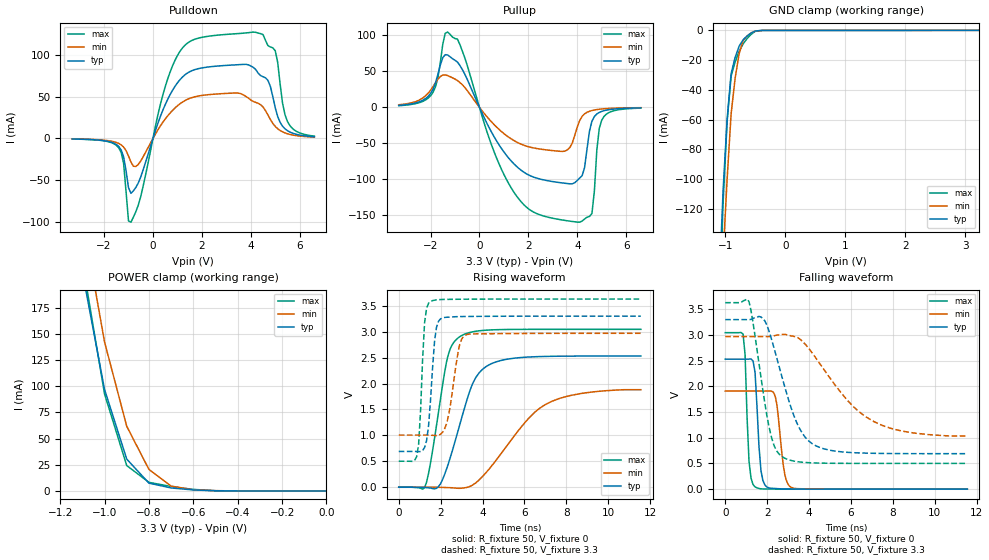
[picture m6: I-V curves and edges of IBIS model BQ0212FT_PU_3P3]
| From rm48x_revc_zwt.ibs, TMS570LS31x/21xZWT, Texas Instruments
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|   Model Cell BQ0212FT_PU_3P3
|BQ0212FT_PU_3P3
[Model]   BQ0212FT_PU_3P3
Model_type   I/O
Polarity   Non-Inverting
Enable   Active-Low
Vinl =  1.15
Vinh =  1.55
Cref =  15.0001pF
Rref =  101.0000M
Vref =  0V
Vmeas =  1.65
C_comp   1.2p   1.2p   1.2p
[Model Spec]
Vinl   1.15   1.02   1.28
Vinh   1.55   1.45   1.65
[Temperature Range]   25   155   -40
[Voltage Range]   3.3   2.97   3.63
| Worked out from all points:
|   slope of the pulldown table from 0 to 0.495 V, typ, clamps not added: 12.4 ohm
|   slope of the pullup table from 0 to 0.495 V, typ, clamps not added: 14.3 ohm
|   GND clamp passes 1 mA (typ) near -0.53 V on its own axis
|   POWER clamp passes 1 mA (typ) near -0.60 V on its own axis
|   rising waveform, R_fixture 50, V_fixture 0: 20-80 % time 1.15ns typ, 2.3ns min, 717ps max; typ from 0 V to 2.53 V
|   rising waveform, R_fixture 50, V_fixture 3.3: 20-80 % time 274ps typ, 441ps min, 219ps max; typ from 0.691 V to 3.3 V
|   falling waveform, R_fixture 50, V_fixture 0: 20-80 % time 219ps typ, 306ps min, 167ps max; typ from 2.53 V to 0 V
|   falling waveform, R_fixture 50, V_fixture 3.3: 20-80 % time 1.2ns typ, 2.39ns min, 725ps max; typ from 3.3 V to 0.691 V
[POWER_clamp]
|   voltage   I(typ)   I(min)   I(max)
-3.3V     3.99A      4.579A     4.788A
-1.1V     209.6mA    262.2mA    219.1mA
-1.067V   172.1mA    222.3mA    177mA
-1.033V   134.5mA    182.3mA    134.9mA
-1V       96.98mA    142.4mA    92.77mA
-900mV    30.42mA    61.81mA    24.22mA
-800mV    7.461mA    20.58mA    8.236mA
-700mV    2.845mA    4.596mA    4.214mA
-600mV    944uA      1.092mA    1.45mA
-500mV    147.5uA    237.2uA    206.1uA
0V        457.2pA    5.75nA     459.6pA
[Pulldown]
|   voltage   I(typ)   I(min)   I(max)
-3.3V     -649.5uA   -582.6uA   -652.5uA
-1.4V     -9.531mA   -5.889mA   -11.14mA
-1.2V     -22.05mA   -10.26mA   -29.81mA
-1V       -58.85mA   -20.91mA   -98.56mA
-900mV    -65.57mA   -28.22mA   -100.1mA
400mV     33.51mA    19.22mA    51.63mA
1.1V      70.16mA    41.36mA    104mA
4.1V      85.11mA    44.32mA    127.2mA
4.7V      69.58mA    28.18mA    111.1mA
5V        36.79mA    14.44mA    104.9mA
5.5V      9.351mA    5.597mA    20.3mA
6.6V      2.027mA    1.639mA    2.825mA
[Pullup]
|   voltage   I(typ)   I(min)   I(max)
-3.3V     2.63mA     3.499mA    2.212mA
-1.9V     24.96mA    28.62mA    20.66mA
-1.3V     72.58mA    44.01mA    104.4mA
-800mV    58.09mA    34.42mA    87.13mA
500mV     -34.83mA   -20.49mA   -52.76mA
1.5V      -81.5mA    -47.85mA   -122.3mA
3.5V      -105.5mA   -60.79mA   -157.1mA
4.1V      -98.13mA   -18.32mA   -159.5mA
4.6V      -19.34mA   -4.48mA    -147.3mA
4.8V      -9.331mA   -3.151mA   -59.41mA
5V        -5.707mA   -2.337mA   -17.88mA
6.6V      -794.7uA   -560.5uA   -1.138mA
[GND_clamp]
|   voltage   I(typ)   I(min)   I(max)
-3.3V     -3.259A    -2.879A    -4.965A
-1.1V     -172mA     -209.5mA   -194.3mA
-1.033V   -107.5mA   -151.2mA   -115.7mA
-966.7mV  -59.82mA   -100mA     -61.12mA
-900mV    -29.02mA   -56.02mA   -30.7mA
-833.3mV  -18.2mA    -32.16mA   -21.26mA
-766.7mV  -10.64mA   -15.72mA   -14.06mA
-700mV    -6.323mA   -6.701mA   -9.103mA
-566.7mV  -1.777mA   -1.727mA   -2.678mA
-500mV    -473.5uA   -571.1uA   -709.6uA
-366.7mV  -40.38uA   -55.9uA    -61.97uA
3.233V    -1.26uA    5.628uA    -10.55uA
[Ramp]
| variable   typ   min   max
dV/dt_f   1.605021/1.221491n   1.205021/2.493272n   1.923433/0.7366147n
dV/dt_r   1.537654/1.159597n   1.158076/2.384517n   1.850348/0.7242663n
R_load = 50
[Rising Waveform]
R_fixture = 50
V_fixture = 0
V_fixture_min = 0
V_fixture_max = 0
|   time   V(typ)   V(min)   V(max)
0s        183.8uV    150.4uV    211uV
1.232ns   -5.293mV   148.7uV    -10.2mV
1.424ns   -10.38mV   218uV      270mV
1.8ns     -20.59mV   2.233uV    1.187V
2.276ns   344.6mV    -5.754mV   2.409V
2.9ns     1.19V      -19.94mV   2.9V
3.684ns   2.122V     86.69mV    3.009V
4.472ns   2.392V     431.5mV    3.036V
7.08ns    2.524V     1.614V     3.046V
11.55ns   2.531V     1.881V     3.046V
[Rising Waveform]
R_fixture = 50
V_fixture = 3.3
V_fixture_min = 2.97
V_fixture_max = 3.63
|   time   V(typ)   V(min)   V(max)
0s        691mV      1.006V     501.8mV
852ps     689.8mV    1.006V     587.5mV
948ps     686.7mV    1.006V     820.2mV
1.232ns   764.2mV    1.006V     3.169V
1.516ns   1.677V     1.005V     3.585V
1.708ns   2.811V     999mV      3.608V
1.896ns   3.2V       1.003V     3.619V
2.34ns    3.28V      1.317V     3.624V
3.152ns   3.294V     2.93V      3.627V
11.55ns   3.3V       2.97V      3.63V
[Falling Waveform]
R_fixture = 50
V_fixture = 0
V_fixture_min = 0
V_fixture_max = 0
|   time   V(typ)   V(min)   V(max)
0s        2.531V     1.91V      3.046V
852ps     2.531V     1.91V      3.017V
1.136ns   2.532V     1.91V      543.9mV
1.424ns   2.272V     1.91V      44.06mV
1.708ns   355.3mV    1.91V      6.964mV
1.992ns   41.14mV    1.91V      3.467mV
2.4ns     13.44mV    1.783V     2.043mV
2.84ns    4.428mV    294.4mV    1.213mV
3.152ns   2.994mV    35.54mV    860.1uV
11.55ns   195.9uV    294.9uV    221.9uV
[Falling Waveform]
R_fixture = 50
V_fixture = 3.3
V_fixture_min = 2.97
V_fixture_max = 3.63
|   time   V(typ)   V(min)   V(max)
0s        3.3V       2.97V      3.63V
1.136ns   3.299V     2.97V      3.65V
1.708ns   3.351V     2.97V      2.174V
2.088ns   3.079V     2.97V      1.218V
2.34ns    2.731V     2.987V     843mV
2.716ns   2.174V     3.01V      633.5mV
3.528ns   1.197V     2.931V     531.2mV
4.472ns   818.4mV    2.468V     508.2mV
7.08ns    698.2mV    1.319V     501.8mV
11.55ns   690.9mV    1.036V     501.7mV
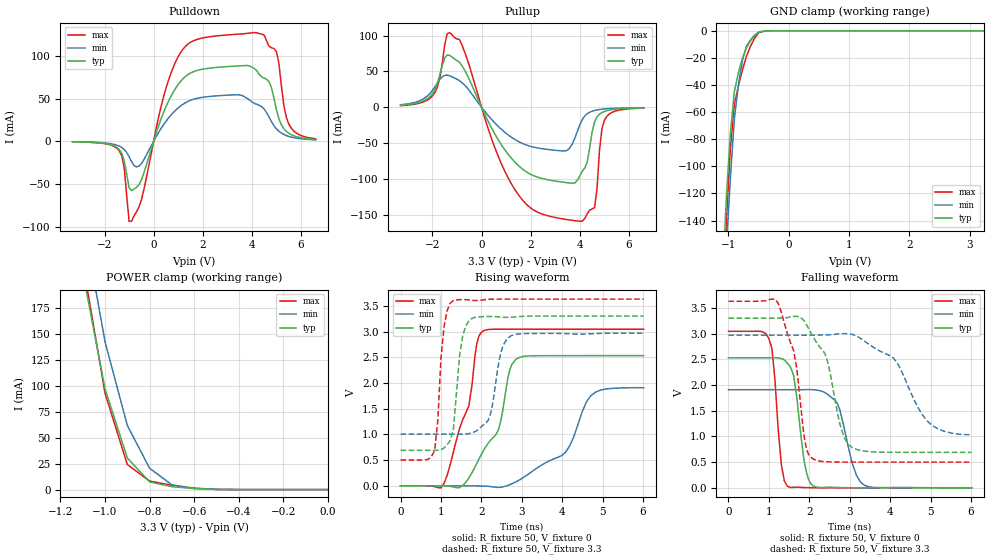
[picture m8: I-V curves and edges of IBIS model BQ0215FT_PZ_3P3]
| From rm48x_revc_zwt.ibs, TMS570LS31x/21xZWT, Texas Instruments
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|   Model Cell BQ0215FT_PZ_3P3
|BQ0215FT_PZ_3P3
[Model]   BQ0215FT_PZ_3P3
Model_type   I/O
Polarity   Non-Inverting
Enable   Active-Low
Vinl =  1.15
Vinh =  1.55
Cref =  15.0001pF
Rref =  101.0000M
Vref =  0V
Vmeas =  1.65
C_comp   1.2p   1.2p   1.2p
[Model Spec]
Vinl   1.15   1.02   1.28
Vinh   1.55   1.45   1.65
[Temperature Range]   25   155   -40
[Voltage Range]   3.3   2.97   3.63
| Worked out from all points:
|   slope of the pulldown table from 0 to 0.495 V, typ, clamps not added: 12.4 ohm
|   slope of the pullup table from 0 to 0.495 V, typ, clamps not added: 14.3 ohm
|   GND clamp passes 1 mA (typ) near -0.50 V on its own axis
|   POWER clamp passes 1 mA (typ) near -0.60 V on its own axis
|   rising waveform, R_fixture 50, V_fixture 0: 20-80 % time 709ps typ, 1.09ns min, 538ps max; typ from 0 V to 2.53 V
|   rising waveform, R_fixture 50, V_fixture 3.3: 20-80 % time 191ps typ, 255ps min, 163ps max; typ from 0.691 V to 3.3 V
|   falling waveform, R_fixture 50, V_fixture 0: 20-80 % time 236ps typ, 354ps min, 181ps max; typ from 2.53 V to 0 V
|   falling waveform, R_fixture 50, V_fixture 3.3: 20-80 % time 544ps typ, 834ps min, 397ps max; typ from 3.3 V to 0.691 V
[POWER_clamp]
|   voltage   I(typ)   I(min)   I(max)
-3.3V     3.99A      4.579A     4.788A
-1.1V     209.6mA    262.2mA    219.1mA
-1.067V   172.1mA    222.3mA    177mA
-1.033V   134.5mA    182.3mA    134.9mA
-1V       96.96mA    142.4mA    92.74mA
-900mV    30.4mA     61.8mA     24.2mA
-800mV    7.444mA    20.57mA    8.211mA
-700mV    2.829mA    4.587mA    4.192mA
-600mV    931uA      1.084mA    1.431mA
-500mV    136.9uA    230.9uA    190.6uA
0V        545.5pA    11.95nA    508.1pA
[Pulldown]
|   voltage   I(typ)   I(min)   I(max)
-3.3V     -654.8uA   -577.8uA   -653.2uA
-1.4V     -9.819mA   -5.703mA   -11.25mA
-1V       -54.51mA   -18.05mA   -93.7mA
-900mV    -57.81mA   -23.76mA   -93.75mA
-500mV    -45.49mA   -26.36mA   -68.8mA
500mV     40.37mA    23.25mA    61.83mA
1.1V      70.16mA    41.36mA    104mA
4.1V      85.11mA    44.32mA    127.2mA
4.7V      69.58mA    28.18mA    111.1mA
5V        36.79mA    14.44mA    104.9mA
5.5V      9.351mA    5.597mA    20.3mA
6.6V      2.027mA    1.639mA    2.825mA
[Pullup]
|   voltage   I(typ)   I(min)   I(max)
-3.3V     2.63mA     3.499mA    2.212mA
-1.9V     24.96mA    28.62mA    20.66mA
-1.3V     72.58mA    44.01mA    104.4mA
-800mV    58.09mA    34.42mA    87.14mA
500mV     -34.83mA   -20.49mA   -52.76mA
1.4V      -78.18mA   -45.94mA   -117.3mA
3.4V      -105.1mA   -61.11mA   -156.5mA
4V        -95.77mA   -24.34mA   -159.4mA
4.3V      -77.12mA   -9.018mA   -149mA
4.6V      -20.57mA   -4.498mA   -140.3mA
5V        -5.887mA   -2.35mA    -18.3mA
6.6V      -811.7uA   -570.8uA   -1.147mA
[GND_clamp]
|   voltage   I(typ)   I(min)   I(max)
-3.3V     -3.262A    -2.882A    -4.97A
-1.1V     -186.6mA   -218.5mA   -219.6mA
-1.033V   -123.2mA   -160.3mA   -142.3mA
-966.7mV  -75.94mA   -109.1mA   -87.15mA
-900mV    -44.75mA   -64.89mA   -54.32mA
-833.3mV  -30.84mA   -39.93mA   -40.67mA
-766.7mV  -20.11mA   -22.06mA   -28.86mA
-700mV    -12.56mA   -11.27mA   -18.88mA
-566.7mV  -3.649mA   -3.348mA   -5.612mA
-500mV    -971.9uA   -1.165mA   -1.458mA
-300mV    -1.282uA   -9.452uA   -1.016uA
3.233V    518.7pA    2.454uA    372.5pA
[Ramp]
| variable   typ   min   max
dV/dt_f   1.58834/0.5671355n   1.196964/0.9000684n   1.903084/0.4078161n
dV/dt_r   1.544202/0.7277083n   1.164767/1.135969n   1.858727/0.5485866n
R_load = 50
[Rising Waveform]
R_fixture = 50
V_fixture = 0
V_fixture_min = 0
V_fixture_max = 0
|   time   V(typ)   V(min)   V(max)
0s        150.7nV    -755.9nV   -19.95nV
1.076ns   -3.282mV   -7.509uV   47.66mV
1.692ns   152.9mV    -1.187mV   1.559V
1.888ns   437.9mV    -2.948mV   2.767V
2.028ns   650.3mV    -3.929mV   3.002V
2.436ns   1.123V     -30.75mV   3.045V
2.86ns    2.464V     78.31mV    3.046V
4.084ns   2.531V     654.5mV    3.046V
4.8ns     2.531V     1.809V     3.046V
6.016ns   2.531V     1.907V     3.046V
[Rising Waveform]
R_fixture = 50
V_fixture = 3.3
V_fixture_min = 2.97
V_fixture_max = 3.63
|   time   V(typ)   V(min)   V(max)
0s        690.7mV    1.006V     501.4mV
844ps     689.5mV    1.006V     684.7mV
1.076ns   733.4mV    1.006V     3.089V
1.308ns   1.102V     1.006V     3.602V
1.536ns   2.905V     1.004V     3.621V
1.768ns   3.255V     1.029V     3.606V
2.208ns   3.292V     1.346V     3.628V
2.484ns   3.281V     2.593V     3.63V
2.712ns   3.278V     2.906V     3.63V
6.016ns   3.3V       2.97V      3.63V
[Falling Waveform]
R_fixture = 50
V_fixture = 0
V_fixture_min = 0
V_fixture_max = 0
|   time   V(typ)   V(min)   V(max)
0s        2.531V     1.91V      3.046V
1ns       2.531V     1.91V      2.906V
1.076ns   2.532V     1.91V      2.715V
1.308ns   2.516V     1.91V      457.4mV
1.46ns    2.424V     1.91V      30.29mV
1.612ns   2.188V     1.91V      8.47mV
2.072ns   54.36mV    1.911V     2.791mV
2.712ns   6.586mV    1.611V     182.4uV
3.368ns   880.9uV    49.4mV     28.63uV
6.016ns   14.15uV    684.6uV    871.1nV
[Falling Waveform]
R_fixture = 50
V_fixture = 3.3
V_fixture_min = 2.97
V_fixture_max = 3.63
|   time   V(typ)   V(min)   V(max)
0s        3.3V       2.97V      3.63V
1.228ns   3.303V     2.97V      3.599V
1.612ns   3.336V     2.97V      2.676V
1.888ns   3.231V     2.97V      927.6mV
2.072ns   2.971V     2.971V     573.5mV
2.392ns   2.603V     2.976V     509.7mV
3.064ns   783.5mV    2.987V     501.9mV
4.084ns   691.5mV    2.525V     501.5mV
5ns       690.7mV    1.243V     501.4mV
6.016ns   690.7mV    1.036V     501.4mV
